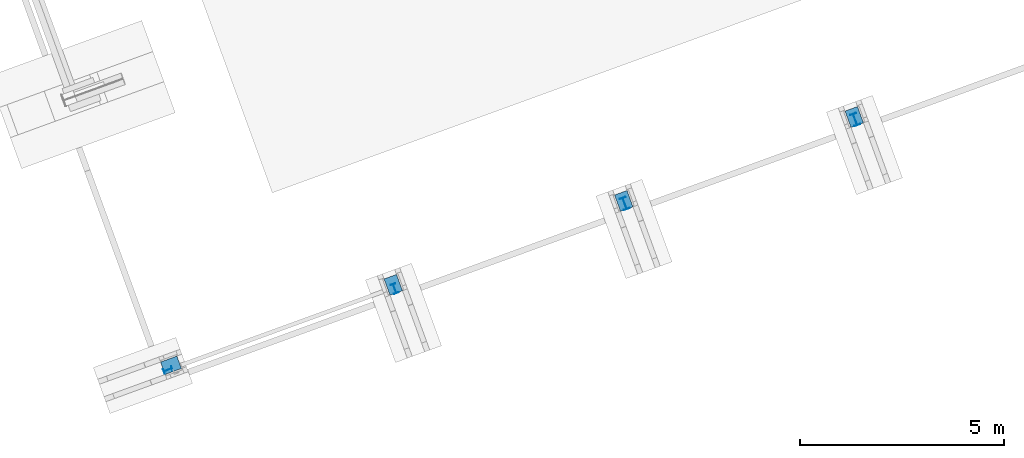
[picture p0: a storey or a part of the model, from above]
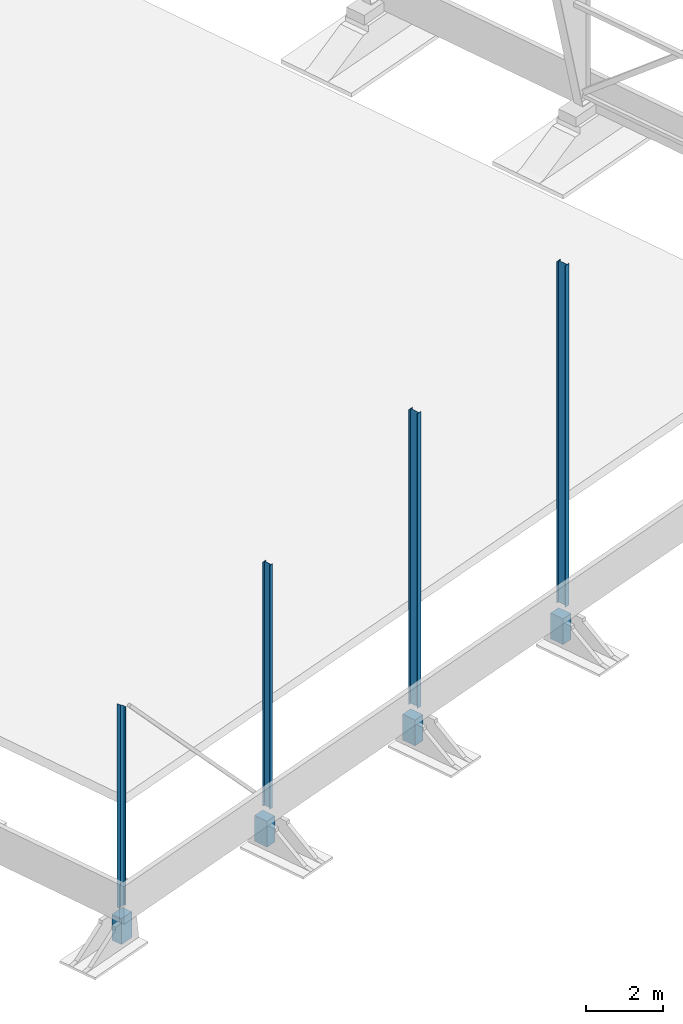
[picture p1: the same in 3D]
Properties of the parts of a building model (IFC4)

# File
Description: ViewDefinition [ReferenceView_V1.2], ExchangeRequirement [Structural], Option[Flat wide beams as plates:On], Option[Location by:BasePoint], Option[Locations from Organizer:On], Option[Layer:Name], Option[Object coloring:ByObjectClass], Option[Export All:Off], Option[Export Pours:Off]
File name: 10664-K-20-V-000.ifc
Time: 2024-03-20T16:07:08
Author: SEPEHERE
Organization: Trimble
Written by: Tekla Structures 2023 Service Pack 8
Made in: IFC Export Version Jan 19 2024
Authorization: IFC4 test model

# IfcSite, Nobelprojektet
RefLatitude: 0, 0, 0; RefLongitude: 0, 0, 0; RefElevation: 0 mm

# IfcBuildingStorey (2)
In: Hall B
Name | Elevation (mm)
Plan_2 | 136000
Plan_1 | 1000

# IfcBeam (134)
Pset_BeamCommon - Status: NEW; IsExternal: no; LoadBearing: no
Name | In | Description | Material = material | length (mm) | height (mm) | width (mm) | volume (m3) | gross surface area (m2) | bottom elevation | top elevation | weight (kg) | Slope (rad) | Roll (rad) | Length (mm) | CrossSectionArea (m2) | OuterSurfaceArea (m2) = GrossSurfaceArea (m2) | NetSurfaceArea (m2) | GrossVolume (m3) | NetVolume (m3) | GrossWeight (kg) | NetWeight (kg)
16 x BEF. STOMME | Plan_2 | IPE400 | S355J2 | 8807.1 | 400 | 180 | 0.07 | 12.9 | +141.851 | +144.517 | 584.2 | 0.2618 | 0 | 8810 | 0.0085 | 12.9 | 13.3 | 0.074 | 0.071 | 584 | 558
4 x BEF. STOMME | Plan_2 | IPE220 | S355J2 | 8966.1 | 220 | 110 | 0.03 | 7.6 | +139.516 | +142.005 | 235.1 | 0.2618 | 0 | 8970 | 0.0033 | 7.6 | 7.72 | 0.03 | 0.029 | 235 | 224
4 x BEF. STOMME | Plan_2 | IPE220 | S355J2 | 9599.3 | 220 | 110 | 0.03 | 8.1 | +141.801 | +144.498 | 251.7 | 0.2618 | 0 | 9600 | 0.0033 | 8.14 | 8.32 | 0.032 | 0.031 | 252 | 241
4 x BEF. STOMME | Plan_2 | IPE120 | S355J2 | 442.3 | 120 | 64 | 0 | 0.2 | +139.450 | +139.680 | 4.6 | 0.26183 | 0 | 442 | 0.0013 | 0.21 | 0.21 | 0.00058 | 0.00055 | 4.58 | 4.28
6 x BEF. STOMME | Plan_2 | KKR80*4 | S355J2 | 7200 | 80 | 80 | 0.01 | 2.2 | +144.267 | +144.365 | 66.1 | 0 | 1.309 | 7200 | 0.0012 | 2.23 | 2.31 | 0.0084 | 0.0088 | 66.1 | 68.7
7 x BEF. STOMME | Plan_2 | KKR80*4 | S355J2 | 7200 | 80 | 80 | 0.01 | 2.2 | +140.301 | +140.399 | 66.1 | 0 | 1.309 | 7200 | 0.0012 | 2.23 | 2.31 | 0.0084 | 0.0088 | 66.1 | 68.7
5 x BEF. STOMME | Plan_2 | KKR120*5 | S355J2 | 7200 | 120 | 120 | 0.03 | 3.3 | +140.071 | +140.218 | 126.6 | 0 | 1.309 | 7200 | 0.0022 | 3.31 | 3.46 | 0.016 | 0.017 | 127 | 130
3 x BEF. STOMME | Plan_2 | KKR80*4 | S355J2 | 7200 | 80 | 80 | 0.01 | 2.2 | +141.404 | +141.502 | 66.1 | 0 | 1.309 | 7200 | 0.0012 | 2.23 | 2.31 | 0.0084 | 0.0088 | 66.1 | 68.7
3 x BEF. STOMME | Plan_2 | KKR80*4 | S355J2 | 7200 | 80 | 80 | 0.01 | 2.2 | +142.456 | +142.554 | 66.1 | 0 | 1.309 | 7200 | 0.0012 | 2.23 | 2.31 | 0.0084 | 0.0088 | 66.1 | 68.7
5 x BEF. STOMME | Plan_2 | KKR80*4 | S355J2 | 7200 | 80 | 80 | 0.01 | 2.2 | +142.456 | +142.554 | 66.1 | 0 | 0.2618 | 7200 | 0.0012 | 2.23 | 2.31 | 0.0084 | 0.0088 | 66.1 | 68.7
3 x BEF. STOMME | Plan_2 | KKR80*4 | S355J2 | 7200 | 80 | 80 | 0.01 | 2.2 | +141.404 | +141.502 | 66.1 | 0 | 0.2618 | 7200 | 0.0012 | 2.23 | 2.31 | 0.0084 | 0.0088 | 66.1 | 68.7
BEF. STOMME | Plan_2 | KKR80*4 | S355J2 | 7850 | 80 | 80 | 0.01 | 2.4 | +144.267 | +144.365 | 72.1 | 0 | 1.309 | 7850 | 0.0012 | 2.43 | 2.51 | 0.0092 | 0.0095 | 72.1 | 74.9
BEF. STOMME | Plan_2 | KKR120*5 | S355J2 | 7850 | 120 | 120 | 0.03 | 3.6 | +140.071 | +140.218 | 138 | 0 | 1.309 | 7850 | 0.0022 | 3.61 | 3.77 | 0.018 | 0.018 | 138 | 142
BEF. STOMME | Plan_2 | KKR80*4 | S355J2 | 7850 | 80 | 80 | 0.01 | 2.4 | +140.301 | +140.399 | 72.1 | 0 | 1.309 | 7850 | 0.0012 | 2.43 | 2.51 | 0.0092 | 0.0095 | 72.1 | 74.9
BEF. STOMME | Plan_2 | KKR80*4 | S355J2 | 7850 | 80 | 80 | 0.01 | 2.4 | +141.404 | +141.502 | 72.1 | 0 | 1.309 | 7850 | 0.0012 | 2.43 | 2.51 | 0.0092 | 0.0095 | 72.1 | 74.9
BEF. STOMME | Plan_2 | KKR80*4 | S355J2 | 7850 | 80 | 80 | 0.01 | 2.4 | +142.456 | +142.554 | 72.1 | 0 | 1.309 | 7850 | 0.0012 | 2.43 | 2.51 | 0.0092 | 0.0095 | 72.1 | 74.9
BEF. STOMME | Plan_2 | KKR80*4 | S355J2 | 7850 | 80 | 80 | 0.01 | 2.4 | +142.456 | +142.554 | 72.1 | 0 | 0.2618 | 7850 | 0.0012 | 2.43 | 2.51 | 0.0092 | 0.0095 | 72.1 | 74.9
BEF. STOMME | Plan_2 | KKR80*4 | S355J2 | 7850 | 80 | 80 | 0.01 | 2.4 | +141.404 | +141.502 | 72.1 | 0 | 0.2618 | 7850 | 0.0012 | 2.43 | 2.51 | 0.0092 | 0.0095 | 72.1 | 74.9
BEF. STOMME | Plan_2 | KKR80*4 | S355J2 | 5900 | 80 | 80 | 0.01 | 1.8 | +144.267 | +144.365 | 54.2 | 0 | 1.309 | 5900 | 0.0012 | 1.83 | 1.89 | 0.0069 | 0.0072 | 54.2 | 56.3
BEF. STOMME | Plan_2 | KKR120*5 | S355J2 | 5900 | 120 | 120 | 0.01 | 2.7 | +140.071 | +140.218 | 103.7 | 0 | 1.309 | 5900 | 0.0022 | 2.71 | 2.83 | 0.013 | 0.015 | 104 | 107
BEF. STOMME | Plan_2 | KKR80*4 | S355J2 | 5900 | 80 | 80 | 0.01 | 1.8 | +140.301 | +140.399 | 54.2 | 0 | 1.309 | 5900 | 0.0012 | 1.83 | 1.89 | 0.0069 | 0.0072 | 54.2 | 56.3
BEF. STOMME | Plan_2 | KKR80*4 | S355J2 | 5900 | 80 | 80 | 0.01 | 1.8 | +142.456 | +142.554 | 54.2 | 0 | 0.2618 | 5900 | 0.0012 | 1.83 | 1.89 | 0.0069 | 0.0072 | 54.2 | 56.3
BEF. STOMME | Plan_2 | KKR80*4 | S355J2 | 7700 | 80 | 80 | 0.01 | 2.4 | +144.267 | +144.365 | 70.7 | 0 | 1.309 | 7700 | 0.0012 | 2.39 | 2.47 | 0.009 | 0.0095 | 70.7 | 73.5
2 x BEF. STOMME | Plan_2 | KKR80*4 | S355J2 | 7700 | 80 | 80 | 0.01 | 2.4 | +140.301 | +140.399 | 70.7 | 0 | 1.309 | 7700 | 0.0012 | 2.39 | 2.47 | 0.009 | 0.0095 | 70.7 | 73.5
2 x BEFINTLIG | Plan_2 | KKR140*5 | S355J2 | 8292.8 | 140 | 140 | 0.03 | 4.5 | +139.593 | +140.885 | 171.9 | 0.13572 | 0.25717 | 8290 | 0.0026 | 4.48 | 4.65 | 0.022 | 0.022 | 172 | 176
2 x BEFINTLIG | Plan_2 | KKR140*5 | S355J2 | 8292.8 | 140 | 140 | 0.03 | 4.5 | +140.739 | +142.024 | 171.9 | 0.13572 | 0.18803 | 8290 | 0.0026 | 4.48 | 4.65 | 0.022 | 0.022 | 172 | 176
2 x BEFINTLIG | Plan_2 | KKR140*5 | S355J2 | 8292.8 | 140 | 140 | 0.03 | 4.5 | +141.916 | +143.207 | 171.9 | 0.13572 | 0.25717 | 8290 | 0.0026 | 4.48 | 4.65 | 0.022 | 0.022 | 172 | 176
2 x BEFINTLIG | Plan_2 | KKR140*5 | S355J2 | 8292.8 | 140 | 140 | 0.03 | 4.5 | +143.062 | +144.346 | 171.9 | 0.13572 | 0.18803 | 8290 | 0.0026 | 4.48 | 4.65 | 0.022 | 0.022 | 172 | 176
2 x BEFINTLIG | Plan_2 | KKR140*5 | S355J2 | 7216.4 | 140 | 140 | 0.03 | 3.9 | +139.593 | +140.885 | 149.6 | 0.15612 | 0.25638 | 7220 | 0.0026 | 3.9 | 4.04 | 0.018 | 0.018 | 150 | 153
2 x BEFINTLIG | Plan_2 | KKR140*5 | S355J2 | 7216.4 | 140 | 140 | 0.03 | 3.9 | +140.740 | +142.024 | 149.6 | 0.15612 | 0.18746 | 7220 | 0.0026 | 3.9 | 4.04 | 0.018 | 0.018 | 150 | 153
2 x BEFINTLIG | Plan_2 | KKR140*5 | S355J2 | 7216.4 | 140 | 140 | 0.03 | 3.9 | +141.916 | +143.207 | 149.6 | 0.15612 | 0.25638 | 7220 | 0.0026 | 3.9 | 4.04 | 0.018 | 0.018 | 150 | 153
2 x BEFINTLIG | Plan_2 | KKR140*5 | S355J2 | 7216.4 | 140 | 140 | 0.03 | 3.9 | +143.062 | +144.346 | 149.6 | 0.15612 | 0.18746 | 7220 | 0.0026 | 3.9 | 4.04 | 0.018 | 0.018 | 150 | 153
5 x BEF. STOMME | Plan_1 | KKR120*5 | S355J2 | 7192 | 120 | 120 | 0.03 | 3.3 | +136.427 | +136.547 | 126.5 | 0 | 1.5708 | 7190 | 0.0022 | 3.31 | 3.46 | 0.016 | 0.017 | 126 | 130
BEF. STOMME | Plan_1 | KKR120*5 | S355J2 | 7370 | 120 | 120 | 0.03 | 3.4 | +136.427 | +136.547 | 129.6 | 0 | 1.5708 | 7370 | 0.0022 | 3.39 | 3.54 | 0.017 | 0.017 | 130 | 133
BEF. STOMME | Plan_1 | KKR140*5 | S355J2 | 7192 | 140 | 140 | 0.03 | 3.9 | +136.417 | +136.557 | 149 | 0 | 1.5708 | 7190 | 0.0026 | 3.88 | 4.04 | 0.018 | 0.018 | 149 | 152
BEF. STOMME | Plan_1 | KKR120*5 | S355J2 | 7550 | 120 | 120 | 0.03 | 3.4 | +136.428 | +136.548 | 132.8 | 0 | 1.5708 | 7550 | 0.0022 | 3.47 | 3.63 | 0.017 | 0.017 | 133 | 136
BEF. STOMME | Plan_1 | KKR120*5 | S355J2 | 5896 | 120 | 120 | 0.01 | 2.7 | +133.345 | +133.465 | 103.7 | 0 | 1.5708 | 5900 | 0.0022 | 2.71 | 2.83 | 0.013 | 0.015 | 104 | 106
BEF. STOMME | Plan_1 | KKR120*5 | S355J2 | 7192 | 120 | 120 | 0.03 | 3.3 | +133.340 | +133.460 | 126.5 | 0 | 1.5708 | 7190 | 0.0022 | 3.31 | 3.46 | 0.016 | 0.017 | 126 | 130
BEF. STOMME | Plan_1 | KKR120*5 | S355J2 | 7510 | 120 | 120 | 0.03 | 3.4 | +137.130 | +137.250 | 132.1 | 0 | 1.5708 | 7510 | 0.0022 | 3.45 | 3.61 | 0.017 | 0.017 | 132 | 136
BEF. STOMME | Plan_1 | KKR120*5 | S355J2 | 5617 | 120 | 120 | 0.01 | 2.6 | +136.427 | +136.547 | 98.8 | 0 | 1.5708 | 5620 | 0.0022 | 2.58 | 2.7 | 0.013 | 0.013 | 98.8 | 101
2 x BEFINTLIG | Plan_1 | L120*12 | S355J2 | 870 | 120 | 120 | 0 | 0.4 | +133.180 | +134.050 | 18.8 | 1.5708 | 0 | 870 | 0.0028 | 0.408 | 0.423 | 0.0024 | 0.0024 | 18.8 | 18.7
16 x BALK | Plan_1 | 310*600 | C25/30 | 800 | 310 | 600 | 0.15 | 1.8 | +132.870 | +133.180 | 372 | 0 | 0 | 800 | 0.186 | 1.83 | 1.83 | 0.149 | 0.149 | 372 | 372
14 x BEFINTLIG | Plan_1 | 310*400 | C25/30 | 400 | 310 | 400 | 0.05 | 0.8 | +132.870 | +133.180 | 124 | 0 | 0 | 400 | 0.124 | 0.816 | 0.816 | 0.05 | 0.05 | 124 | 124

# IfcColumn (32)
In: Plan_1
Pset_ColumnCommon - Status: NEW; IsExternal: no; LoadBearing: no; Slope: 1.5708 rad; Roll: 0 rad
Name | Description = diameter/profile | Material = material | length (mm) | volume (m3) | bottom elevation | top elevation | weight (kg) | Length (mm) | CrossSectionArea (m2) | OuterSurfaceArea (m2) = GrossSurfaceArea (m2) | NetSurfaceArea (m2) | GrossVolume (m3) | NetVolume (m3) | GrossWeight (kg) | NetWeight (kg)
14 x BEF. GRUND | 425*324 | C25/30 | 820 | 0.11 | +132.050 | +132.870 | 282.3 | 820 | 0.138 | 1.5 | 1.5 | 0.113 | 0.113 | 282 | 282
4 x BEF. STOMME | IPE220 | S355J2 | 6481.1 | 0.03 | +133.180 | +139.661 | 169.9 | 6480 | 0.0033 | 5.5 | 5.56 | 0.022 | 0.022 | 170 | 161
4 x BEF. STOMME | IPE240 | S355J2 | 7762.3 | 0.03 | +133.195 | +140.957 | 238.2 | 7760 | 0.0039 | 7.16 | 7.36 | 0.03 | 0.029 | 238 | 227
4 x BEF. STOMME | IPE300 | S355J2 | 9369.9 | 0.05 | +133.195 | +142.565 | 395.7 | 9370 | 0.0054 | 10.9 | 11.1 | 0.05 | 0.049 | 396 | 382
2 x BEF. STOMME | IPE300 | S355J2 | 10863.2 | 0.05 | +133.195 | +144.058 | 458.8 | 10900 | 0.0054 | 12.6 | 12.9 | 0.058 | 0.056 | 459 | 442
BEFINTLIG | KKR120*5 | S355J2 | 3940 | 0.01 | +133.180 | +137.120 | 69.3 | 3940 | 0.0022 | 1.81 | 1.89 | 0.0088 | 0.0091 | 69.3 | 71.1
BEFINTLIG | KKR120*5 | S355J2 | 3975 | 0.01 | +133.145 | +137.120 | 69.9 | 3980 | 0.0022 | 1.83 | 1.91 | 0.0088 | 0.0091 | 69.9 | 71.8
2 x BEFINTLIG | L120*12 | S355J2 | 870 | 0 | +133.180 | +134.050 | 18.8 | 870 | 0.0028 | 0.408 | 0.423 | 0.0024 | 0.0024 | 18.8 | 18.7

# IfcElementAssembly (484)
Pset_ElementAssemblyCommon - Status: NEW
Name | In | Reference
226 x BEF. STOMME | Plan_2 | B/0(?)
26 x BEF. STOMME | Plan_2 | A/0(?)
PRIMÄR_BALK | Plan_2 | B/0(?)
15 x BEFINTLIG | Plan_2 | B/0(?)
3 x BJÄLKLAG | Plan_1 | BJL/0(?)
74 x BEF_GRUND | Plan_1 | BJL/0(?)
18 x BALK | Plan_1 | B/0(?)
13 x BEF. GRUND | Plan_1 | B/0(?)
76 x BEF. STOMME | Plan_1 | B/0(?)
6 x BEF. STOMME | Plan_1 | A/0(?)
2 x PRIMÄR_BALK | Plan_1 | B/0(?)
19 x BEFINTLIG | Plan_1 | B/0(?)
BEFINTLIG | Plan_1 | BJL/0(?)
4 x YV99 | Plan_1 | A/0(?)

# IfcMember (122)
Material: S355J2
Pset_MemberCommon - Status: NEW; IsExternal: no; LoadBearing: no
Name | In | Description | Slope (rad) | Roll (rad) | Length (mm) | CrossSectionArea (m2) | OuterSurfaceArea (m2) = GrossSurfaceArea (m2) | NetSurfaceArea (m2) | GrossVolume (m3) | NetVolume (m3) | GrossWeight (kg) | NetWeight (kg)
32 x BEF. STOMME | Plan_2 | BL300*25 | 0.65424 | 0.91655 | 1980 | 0.0075 | 1.3 | 1.3 | 0.015 | 0.015 | 117 | 117
16 x BEF. STOMME | Plan_2 | BL300*20 | 0.39554 | 1.17525 | 8730 | 0.006 | 5.6 | 5.6 | 0.052 | 0.052 | 411 | 411
16 x BEF. STOMME | Plan_2 | BL100*15 | 1.309 | 0.2618 | 1290 | 0.0015 | 0.299 | 0.299 | 0.0019 | 0.0019 | 15.2 | 15.2
16 x BEF. STOMME | Plan_2 | BL100*15 | 1.309 | 0.2618 | 883 | 0.0015 | 0.206 | 0.206 | 0.0013 | 0.0013 | 10.4 | 10.4
16 x BEF. STOMME | Plan_2 | BL100*15 | 1.30899 | 0.26181 | 614 | 0.0015 | 0.144 | 0.144 | 0.00092 | 0.00092 | 7.24 | 7.24
4 x BEF. STOMME | Plan_2 | BL300*15 | 0.65451 | 0.91629 | 290 | 0.0045 | 0.192 | 0.192 | 0.0013 | 0.0013 | 10.2 | 10.2
16 x BEF. STOMME | Plan_1 | BL300*15 | 1.33898 | 0.23182 | 5400 | 0.0045 | 3.41 | 3.41 | 0.024 | 0.024 | 191 | 191
2 x BEF. STOMME | Plan_1 | KKR100*4 | 0.82436 | 0.74644 | 8020 | 0.0015 | 3.13 | 3.21 | 0.012 | 0.012 | 93.8 | 96.7
2 x BEF. STOMME | Plan_1 | KKR160*6 | 0.6833 | 0.88749 | 9080 | 0.0037 | 5.54 | 5.82 | 0.034 | 0.034 | 267 | 263
BEF. STOMME | Plan_1 | KKR160*6 | 0.77818 | 0.79262 | 8060 | 0.0037 | 4.92 | 5.16 | 0.03 | 0.029 | 237 | 234
BEF. STOMME | Plan_1 | KKR160*6 | 0.77901 | 0.79179 | 8060 | 0.0037 | 4.92 | 5.16 | 0.03 | 0.029 | 237 | 234

# IfcPlate (114)
Material: S355J2
Name | In | Description | Pset_PlateCommon, Status | Pset_PlateCommon, IsExternal = Pset_PlateCommon, LoadBearing | Width (mm) | GrossArea (m2) | NetArea (m2) | SideArea (m2) | Qto_PlateBaseQuantities, GrossVolume (m3) = Qto_PlateBaseQuantities, NetVolume (m3) | Qto_PlateBaseQuantities, GrossWeight (kg) | Qto_PlateBaseQuantities, NetWeight (kg) | Perimeter (mm)
16 x BEF. STOMME | Plan_2 | BL300*20 | NEW | no | 20 | 6.31 | 6.31 | 5.91 | 0.059 | 463 | 463 | 0
16 x BEF. STOMME | Plan_2 | PL8 | NEW | no | 8 | 15 | 18.3 | 18.2 | 0.073 | 943 | 570 | 20900
16 x BEF. STOMME | Plan_2 | BL300*20 | NCC-LOD - Pelare - length: 510 mm; volume: 0 m3; bottom elevation: +143.974; top elevation: +144.484; material: S355J2; weight: 24 kg; diameter/profile: BL300*20; Pset_ColumnCommon - Status: NEW; IsExternal: no; LoadBearing: no; Slope: 1.5708 rad; Roll: 0 rad; Qto_ColumnBaseQuantities - Length: 510 mm; CrossSectionArea: 0.006 m2; OuterSurfaceArea: 0.338 m2; GrossSurfaceArea: 0.338 m2; NetSurfaceArea: 0.338 m2; GrossVolume: 0.0031 m3; NetVolume: 0.0031 m3; GrossWeight: 24 kg; NetWeight: 24 kg
10 x BEF. STOMME | Plan_2 | BL300*15 | NCC-LOD - Pelare - length: 6473.5 mm; volume: 0.03 m3; bottom elevation: +133.200; top elevation: +139.673; material: S355J2; weight: 228.7 kg; diameter/profile: BL300*15; Pset_ColumnCommon - Status: NEW; IsExternal: no; LoadBearing: no; Slope: 1.5708 rad; Roll: 0 rad; Qto_ColumnBaseQuantities - Length: 6470 mm; CrossSectionArea: 0.0045 m2; OuterSurfaceArea: 4.09 m2; GrossSurfaceArea: 4.09 m2; NetSurfaceArea: 4.09 m2; GrossVolume: 0.03 m3; NetVolume: 0.029 m3; GrossWeight: 229 kg; NetWeight: 229 kg
10 x BEF. STOMME | Plan_2 | BL100*15 | NEW | no | 15 | 0.248 | 0.248 | 0.216 | 0.0016 | 12.5 | 12.5 | 0
10 x BEF. STOMME | Plan_2 | PL8 | NEW | no | 8 | 9.89 | 11.5 | 11.5 | 0.046 | 621 | 359 | 14100
16 x BEF. STOMME | Plan_1 | BL300*20 | NEW | no | 20 | 0.207 | 0.207 | 0.195 | 0.0019 | 14.3 | 14.3 | 0
6 x BEF. STOMME | Plan_1 | BL300*15 | NCC-LOD - Pelare - length: 6473.5 mm; volume: 0.03 m3; bottom elevation: +133.200; top elevation: +139.673; material: S355J2; weight: 228.7 kg; diameter/profile: BL300*15; Pset_ColumnCommon - Status: NEW; IsExternal: no; LoadBearing: no; Slope: 1.5708 rad; Roll: 0 rad; Qto_ColumnBaseQuantities - Length: 6470 mm; CrossSectionArea: 0.0045 m2; OuterSurfaceArea: 4.09 m2; GrossSurfaceArea: 4.09 m2; NetSurfaceArea: 4.09 m2; GrossVolume: 0.03 m3; NetVolume: 0.029 m3; GrossWeight: 229 kg; NetWeight: 229 kg
6 x BEF. STOMME | Plan_1 | BL100*15 | NEW | no | 15 | 0.248 | 0.248 | 0.216 | 0.0016 | 12.5 | 12.5 | 0
6 x BEF. STOMME | Plan_1 | PL8 | NEW | no | 8 | 9.89 | 11.5 | 11.5 | 0.046 | 621 | 359 | 14100
2 x BEFINTLIG | Plan_1 | BL110*15 | NEW | no | 15 | 0.053 | 0.053 | 0.047 | 0.00033 | 2.59 | 2.59 | 0

# IfcSlab (78)
In: Plan_1
Material: C25/30
NCC-LOD - Platta-Bjälklag - material: C25/30
Pset_SlabCommon - IsExternal: no; LoadBearing: no; Status: NEW; Combustible: no; Compartmentation: no
Name | Description = height (mm) = Depth (mm) | weight (kg) | length (mm) | width (mm) | net volume (m3) | gross volume (m3) | perimeter (mm) | gross area (m2) = net area (m2) | top elevation | bottom elevation | Length (mm) | Width (mm) | GrossArea (m2) | NetArea (m2) | SideArea (m2) | GrossVolume (m3) | NetVolume (m3) | GrossWeight (kg) | NetWeight (kg) | Perimeter (mm)
14 x BEF_GRUND | 70 | 451.5 | 2150 | 1200 | 0.2 | 0.2 | 6700 | 2.6 | +132.050 | +131.980 | 2150 | 1200 | 2.58 | 5.63 | 5.33 | 0.181 | 0.181 | 452 | 452 | 6700
28 x BEF_GRUND | 130 | 356.2 | 2150 | 820 | 0.1 | 0.1 | 5525.9 | 1.1 | +132.870 | +132.050 | 2150 | 820 | 1.76 | 2.91 | 2.52 | 0.142 | 0.142 | 573 | 356 | 5530
16 x BEF_GRUND | 130 | 3120 | 4000 | 2400 | 1.2 | 1.2 | 12800 | 9.6 | +131.970 | +131.840 | 4000 | 2400 | 9.6 | 20.9 | 19.8 | 1.25 | 1.25 | 3120 | 3120 | 12800
16 x BEF_GRUND | 785 | 4171.4 | 4000 | 900 | 1.7 | 1.7 | 8697.2 | 2.1 | +132.870 | +131.970 | 4000 | 900 | 3.6 | 11.1 | 6.86 | 1.67 | 1.67 | 7060 | 4170 | 8700
BEF_GRUND | 300 | 1221182 | 58110 | 28020 | 488.5 | 488.5 | 172260 | 1628.2 | +133.180 | +132.880 | 58100 | 28000 | 1630 | 3310 | 3270 | 488 | 488 | 1220000 | 1220000 | 172000
BEFINTLIG | 4200 | 5460.5 | 4112.5 | 248.9 | 2.2 | 2.4 | 8646.4 | 0.6 | +133.180 | +132.910 | 4110 | 249 | 1.02 | 37.3 | 4.8 | 2.4 | 2.18 | 10700 | 5460 | 8650
2 x BEFINTLIG | 450 | 2.3 | 270 | 15 | 0 | 0 | 555.4 | 0 | +133.130 | +133.115 | 270 | 15 | 0.004 | 0.254 | 0.011 | 0.00092 | 0.00092 | 4.56 | 2.28 | 555

# IfcVoidingFeature (39)
PredefinedType: HOLE
Name | In | Description
16 x CUTPART | Plan_2 | BL185
8 x CUTPART | Plan_2 | BL115
4 x CUTPART | Plan_2 | BL69
4 x CUTPART | Plan_1 | BL115
CUTPART | Plan_1 | BL4000
2 x Öxx | Plan_1 | 950*1100
Öxx | Plan_1 | 939.95462536*3500
Öxx | Plan_1 | 949.95462536*1099.03844161
2 x Öxx | Plan_1 | 949.95462536*1100

# IfcWall (4)
In: Plan_1
Description: 1200*150; Material: Concrete_Undefined
NCC-LOD - Vägg - height: 1200 mm; thickness: 150 mm; material: Concrete_Undefined
Pset_WallCommon - Status: NEW; IsExternal: no; LoadBearing: no; Combustible: no; Compartmentation: no; ExtendToStructure: no
Qto_WallBaseQuantities - Width: 150 mm; Height: 1200 mm
Name | length (mm) | gross area (m2) | net area (m2) | weight (kg) | Length (mm) | NetSideArea (m2) | NetFootprintArea (m2) | GrossVolume (m3) | NetVolume (m3) | GrossWeight (kg) | NetWeight (kg)
BEFINTLIG | 65100 | 76.1 | 78.1 | 28548.4 | 65100 | 153 | 9.76 | 11.7 | 11.4 | 29300 | 28500
BEFINTLIG | 36300 | 43.6 | 43.6 | 16335 | 36300 | 87.5 | 5.44 | 6.53 | 6.53 | 16300 | 16300
BEFINTLIG | 65100 | 72 | 78.1 | 27000.7 | 65100 | 145 | 9.76 | 11.7 | 10.8 | 29300 | 27000
BEFINTLIG | 36150 | 43.4 | 43.4 | 16267.5 | 36100 | 87.1 | 5.42 | 6.51 | 6.51 | 16300 | 16300
